VERSION 5.7 ;
  NOWIREEXTENSIONATPIN ON ;
  DIVIDERCHAR "/" ;
  BUSBITCHARS "[]" ;
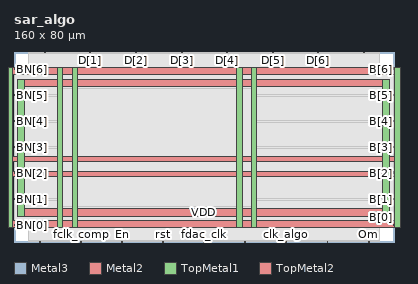
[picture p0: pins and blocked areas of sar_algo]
MACRO sar_algo
  CLASS BLOCK ;
  FOREIGN sar_algo ;
  ORIGIN 0.000 0.000 ;
  SIZE 160.000 BY 80.000 ;
  PIN BN[0]
    DIRECTION OUTPUT ;
    USE SIGNAL ;
    ANTENNADIFFAREA 0.708600 ;
    PORT
      LAYER Metal3 ;
        RECT 0.000 6.940 0.400 7.340 ;
    END
  END BN[0]
  PIN BN[1]
    DIRECTION OUTPUT ;
    USE SIGNAL ;
    ANTENNADIFFAREA 0.708600 ;
    PORT
      LAYER Metal3 ;
        RECT 0.000 17.860 0.400 18.260 ;
    END
  END BN[1]
  PIN BN[2]
    DIRECTION OUTPUT ;
    USE SIGNAL ;
    ANTENNADIFFAREA 0.708600 ;
    PORT
      LAYER Metal3 ;
        RECT 0.000 28.780 0.400 29.180 ;
    END
  END BN[2]
  PIN BN[3]
    DIRECTION OUTPUT ;
    USE SIGNAL ;
    ANTENNADIFFAREA 0.708600 ;
    PORT
      LAYER Metal3 ;
        RECT 0.000 39.700 0.400 40.100 ;
    END
  END BN[3]
  PIN BN[4]
    DIRECTION OUTPUT ;
    USE SIGNAL ;
    ANTENNADIFFAREA 0.708600 ;
    PORT
      LAYER Metal3 ;
        RECT 0.000 50.620 0.400 51.020 ;
    END
  END BN[4]
  PIN BN[5]
    DIRECTION OUTPUT ;
    USE SIGNAL ;
    ANTENNADIFFAREA 0.708600 ;
    PORT
      LAYER Metal3 ;
        RECT 0.000 61.540 0.400 61.940 ;
    END
  END BN[5]
  PIN BN[6]
    DIRECTION OUTPUT ;
    USE SIGNAL ;
    ANTENNADIFFAREA 0.708600 ;
    PORT
      LAYER Metal3 ;
        RECT 0.000 72.460 0.400 72.860 ;
    END
  END BN[6]
  PIN B[0]
    DIRECTION OUTPUT ;
    USE SIGNAL ;
    ANTENNADIFFAREA 0.708600 ;
    PORT
      LAYER Metal3 ;
        RECT 159.600 6.940 160.000 7.340 ;
    END
  END B[0]
  PIN B[1]
    DIRECTION OUTPUT ;
    USE SIGNAL ;
    ANTENNADIFFAREA 0.708600 ;
    PORT
      LAYER Metal3 ;
        RECT 159.600 17.860 160.000 18.260 ;
    END
  END B[1]
  PIN B[2]
    DIRECTION OUTPUT ;
    USE SIGNAL ;
    ANTENNADIFFAREA 0.708600 ;
    PORT
      LAYER Metal3 ;
        RECT 159.600 28.780 160.000 29.180 ;
    END
  END B[2]
  PIN B[3]
    DIRECTION OUTPUT ;
    USE SIGNAL ;
    ANTENNADIFFAREA 0.708600 ;
    PORT
      LAYER Metal3 ;
        RECT 159.600 39.700 160.000 40.100 ;
    END
  END B[3]
  PIN B[4]
    DIRECTION OUTPUT ;
    USE SIGNAL ;
    ANTENNADIFFAREA 0.708600 ;
    PORT
      LAYER Metal3 ;
        RECT 159.600 50.620 160.000 51.020 ;
    END
  END B[4]
  PIN B[5]
    DIRECTION OUTPUT ;
    USE SIGNAL ;
    ANTENNADIFFAREA 0.708600 ;
    PORT
      LAYER Metal3 ;
        RECT 159.600 61.540 160.000 61.940 ;
    END
  END B[5]
  PIN B[6]
    DIRECTION OUTPUT ;
    USE SIGNAL ;
    ANTENNADIFFAREA 0.708600 ;
    PORT
      LAYER Metal3 ;
        RECT 159.600 72.460 160.000 72.860 ;
    END
  END B[6]
  PIN D[0]
    DIRECTION OUTPUT ;
    USE SIGNAL ;
    ANTENNADIFFAREA 0.708600 ;
    PORT
      LAYER Metal2 ;
        RECT 12.760 79.600 13.160 80.000 ;
    END
  END D[0]
  PIN D[1]
    DIRECTION OUTPUT ;
    USE SIGNAL ;
    ANTENNADIFFAREA 0.708600 ;
    PORT
      LAYER Metal2 ;
        RECT 31.960 79.600 32.360 80.000 ;
    END
  END D[1]
  PIN D[2]
    DIRECTION OUTPUT ;
    USE SIGNAL ;
    ANTENNADIFFAREA 0.708600 ;
    PORT
      LAYER Metal2 ;
        RECT 51.160 79.600 51.560 80.000 ;
    END
  END D[2]
  PIN D[3]
    DIRECTION OUTPUT ;
    USE SIGNAL ;
    ANTENNADIFFAREA 0.708600 ;
    PORT
      LAYER Metal2 ;
        RECT 70.360 79.600 70.760 80.000 ;
    END
  END D[3]
  PIN D[4]
    DIRECTION OUTPUT ;
    USE SIGNAL ;
    ANTENNADIFFAREA 0.708600 ;
    PORT
      LAYER Metal2 ;
        RECT 89.560 79.600 89.960 80.000 ;
    END
  END D[4]
  PIN D[5]
    DIRECTION OUTPUT ;
    USE SIGNAL ;
    ANTENNADIFFAREA 0.708600 ;
    PORT
      LAYER Metal2 ;
        RECT 108.760 79.600 109.160 80.000 ;
    END
  END D[5]
  PIN D[6]
    DIRECTION OUTPUT ;
    USE SIGNAL ;
    ANTENNADIFFAREA 0.708600 ;
    PORT
      LAYER Metal2 ;
        RECT 127.960 79.600 128.360 80.000 ;
    END
  END D[6]
  PIN D[7]
    DIRECTION OUTPUT ;
    USE SIGNAL ;
    ANTENNADIFFAREA 0.708600 ;
    PORT
      LAYER Metal2 ;
        RECT 147.160 79.600 147.560 80.000 ;
    END
  END D[7]
  PIN En
    DIRECTION INPUT ;
    USE SIGNAL ;
    ANTENNAGATEAREA 0.180700 ;
    PORT
      LAYER Metal2 ;
        RECT 45.400 0.000 45.800 0.400 ;
    END
  END En
  PIN Om
    DIRECTION INPUT ;
    USE SIGNAL ;
    ANTENNAGATEAREA 0.180700 ;
    PORT
      LAYER Metal2 ;
        RECT 149.080 0.000 149.480 0.400 ;
    END
  END Om
  PIN Op
    DIRECTION INPUT ;
    USE SIGNAL ;
    ANTENNAGATEAREA 0.180700 ;
    PORT
      LAYER Metal2 ;
        RECT 10.840 0.000 11.240 0.400 ;
    END
  END Op
  PIN VDD
    DIRECTION INPUT ;
    USE POWER ;
    PORT
      LAYER TopMetal1 ;
        RECT 1.560 10.920 4.560 68.460 ;
    END
    PORT
      LAYER TopMetal1 ;
        RECT 155.280 10.920 158.280 68.460 ;
    END
    PORT
      LAYER TopMetal2 ;
        RECT 1.560 10.920 158.280 13.920 ;
    END
    PORT
      LAYER TopMetal2 ;
        RECT 1.560 65.460 158.280 68.460 ;
    END
    PORT
      LAYER TopMetal1 ;
        RECT 18.260 5.920 20.460 73.460 ;
    END
    PORT
      LAYER TopMetal1 ;
        RECT 93.860 5.920 96.060 73.460 ;
    END
    PORT
      LAYER TopMetal2 ;
        RECT -3.440 27.620 163.280 29.820 ;
    END
  END VDD
  PIN VSS
    DIRECTION INPUT ;
    USE GROUND ;
    PORT
      LAYER TopMetal1 ;
        RECT -3.440 5.920 -0.440 73.460 ;
    END
    PORT
      LAYER TopMetal1 ;
        RECT 160.280 5.920 163.280 73.460 ;
    END
    PORT
      LAYER TopMetal2 ;
        RECT -3.440 5.920 163.280 8.920 ;
    END
    PORT
      LAYER TopMetal2 ;
        RECT -3.440 70.460 163.280 73.460 ;
    END
    PORT
      LAYER TopMetal1 ;
        RECT 24.460 5.920 26.660 73.460 ;
    END
    PORT
      LAYER TopMetal1 ;
        RECT 100.060 5.920 102.260 73.460 ;
    END
    PORT
      LAYER TopMetal2 ;
        RECT -3.440 33.820 163.280 36.020 ;
    END
  END VSS
  PIN clk_algo
    DIRECTION INPUT ;
    USE SIGNAL ;
    ANTENNAGATEAREA 0.180700 ;
    PORT
      LAYER Metal2 ;
        RECT 114.520 0.000 114.920 0.400 ;
    END
  END clk_algo
  PIN fclk_comp
    DIRECTION OUTPUT ;
    USE SIGNAL ;
    ANTENNADIFFAREA 0.708600 ;
    PORT
      LAYER Metal2 ;
        RECT 28.120 0.000 28.520 0.400 ;
    END
  END fclk_comp
  PIN fclk_in
    DIRECTION INPUT ;
    USE SIGNAL ;
    ANTENNAGATEAREA 2.901600 ;
    PORT
      LAYER Metal2 ;
        RECT 97.240 0.000 97.640 0.400 ;
    END
  END fclk_in
  PIN fclk_samp
    DIRECTION OUTPUT ;
    USE SIGNAL ;
    ANTENNADIFFAREA 0.708600 ;
    PORT
      LAYER Metal2 ;
        RECT 131.800 0.000 132.200 0.400 ;
    END
  END fclk_samp
  PIN fdac_clk
    DIRECTION OUTPUT ;
    USE SIGNAL ;
    ANTENNADIFFAREA 0.708600 ;
    PORT
      LAYER Metal2 ;
        RECT 79.960 0.000 80.360 0.400 ;
    END
  END fdac_clk
  PIN rst
    DIRECTION INPUT ;
    USE SIGNAL ;
    ANTENNAGATEAREA 0.180700 ;
    PORT
      LAYER Metal2 ;
        RECT 62.680 0.000 63.080 0.400 ;
    END
  END rst
  OBS
      LAYER GatPoly ;
        RECT 5.760 14.970 154.080 64.410 ;
      LAYER Metal1 ;
        RECT 5.760 14.900 154.080 64.480 ;
      LAYER Metal2 ;
        RECT 6.135 79.390 12.550 79.600 ;
        RECT 13.370 79.390 31.750 79.600 ;
        RECT 32.570 79.390 50.950 79.600 ;
        RECT 51.770 79.390 70.150 79.600 ;
        RECT 70.970 79.390 89.350 79.600 ;
        RECT 90.170 79.390 108.550 79.600 ;
        RECT 109.370 79.390 127.750 79.600 ;
        RECT 128.570 79.390 146.950 79.600 ;
        RECT 147.770 79.390 153.705 79.600 ;
        RECT 6.135 0.610 153.705 79.390 ;
        RECT 6.135 0.100 10.630 0.610 ;
        RECT 11.450 0.100 27.910 0.610 ;
        RECT 28.730 0.100 45.190 0.610 ;
        RECT 46.010 0.100 62.470 0.610 ;
        RECT 63.290 0.100 79.750 0.610 ;
        RECT 80.570 0.100 97.030 0.610 ;
        RECT 97.850 0.100 114.310 0.610 ;
        RECT 115.130 0.100 131.590 0.610 ;
        RECT 132.410 0.100 148.870 0.610 ;
        RECT 149.690 0.100 153.705 0.610 ;
      LAYER Metal3 ;
        RECT 0.610 72.250 159.390 72.760 ;
        RECT 0.400 62.150 159.600 72.250 ;
        RECT 0.610 61.330 159.390 62.150 ;
        RECT 0.400 51.230 159.600 61.330 ;
        RECT 0.610 50.410 159.390 51.230 ;
        RECT 0.400 40.310 159.600 50.410 ;
        RECT 0.610 39.490 159.390 40.310 ;
        RECT 0.400 29.390 159.600 39.490 ;
        RECT 0.610 28.570 159.390 29.390 ;
        RECT 0.400 18.470 159.600 28.570 ;
        RECT 0.610 17.650 159.390 18.470 ;
        RECT 0.400 7.550 159.600 17.650 ;
        RECT 0.610 7.040 159.390 7.550 ;
      LAYER Metal4 ;
        RECT 18.440 14.975 102.080 64.405 ;
      LAYER Metal5 ;
        RECT 18.395 14.810 102.125 64.570 ;
  END
END sar_algo
END LIBRARY

